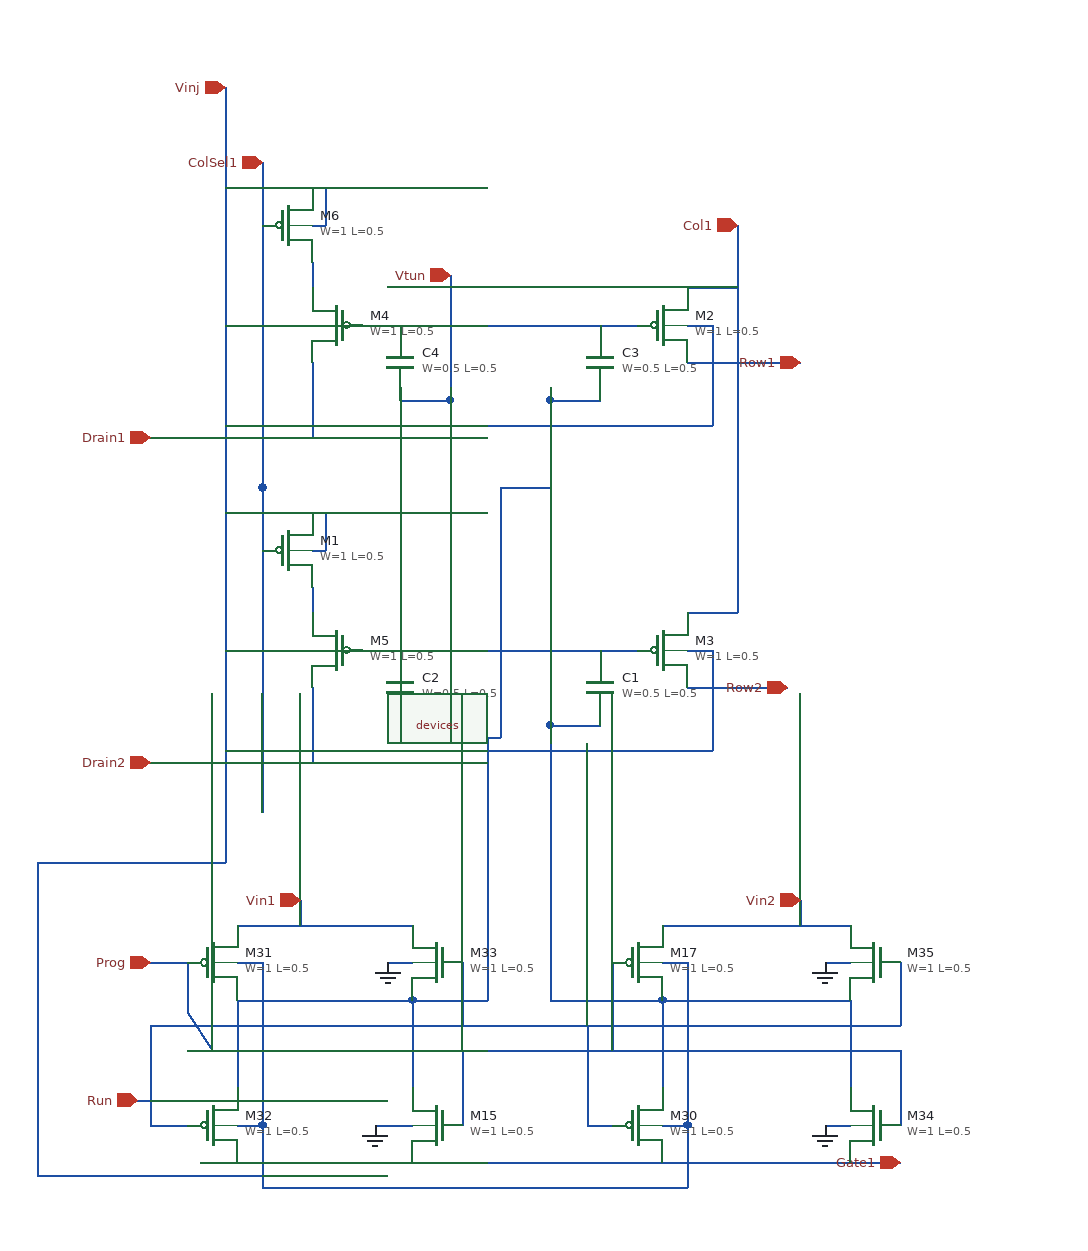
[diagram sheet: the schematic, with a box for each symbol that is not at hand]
v {xschem version=2.9.9 file_version=1.2 }
G {}
K {}
V {}
S {}
E {}
N 1300 -1430 1330 -1430 { lab=#net1}
N 1260 -1380 1260 -1370 { lab=#net2}
N 1260 -1370 1300 -1370 { lab=#net2}
N 1140 -1430 1300 -1430 { lab=#net1}
N 1140 -1370 1180 -1370 { lab=Vtun}
N 1140 -1380 1140 -1370 { lab=Vtun}
N 1110 -1430 1140 -1430 { lab=#net1}
N 1070 -1480 1070 -1460 { lab=#net3}
N 1260 -1370 1260 -1300 { lab=#net2}
N 1180 -1380 1180 -1370 { lab=Vtun}
N 1180 -1560 1180 -1370 { lab=Vtun}
N 1030 -1560 1030 -1510 { lab=ColSel1}
N 1030 -1560 1030 -1300 { lab=ColSel1}
N 1070 -1400 1070 -1340 { lab=Drain2}
N 950 -1340 1070 -1340 { lab=Drain2}
N 1000 -1560 1000 -1300 { lab=Vinj}
N 1000 -1540 1070 -1540 { lab=Vinj}
N 1300 -1690 1330 -1690 { lab=#net4}
N 1260 -1640 1260 -1630 { lab=#net5}
N 1260 -1630 1300 -1630 { lab=#net5}
N 1140 -1690 1300 -1690 { lab=#net4}
N 1140 -1630 1180 -1630 { lab=Vtun}
N 1140 -1640 1140 -1630 { lab=Vtun}
N 1110 -1690 1140 -1690 { lab=#net4}
N 1070 -1740 1070 -1720 { lab=#net6}
N 1370 -1720 1410 -1720 { lab=Col1}
N 1260 -1630 1260 -1560 { lab=#net5}
N 1180 -1640 1180 -1630 { lab=Vtun}
N 1180 -1630 1180 -1560 { lab=Vtun}
N 1030 -1820 1030 -1770 { lab=ColSel1}
N 1030 -1820 1030 -1560 { lab=ColSel1}
N 1070 -1660 1070 -1600 { lab=Drain1}
N 950 -1600 1070 -1600 { lab=Drain1}
N 1000 -1820 1000 -1560 { lab=Vinj}
N 1000 -1800 1070 -1800 { lab=Vinj}
N 930 -1600 960 -1600 { lab=Drain1}
N 930 -1340 960 -1340 { lab=Drain2}
N 1000 -1690 1070 -1690 { lab=Vinj}
N 1070 -1770 1080 -1770 { lab=Vinj}
N 1080 -1800 1080 -1770 { lab=Vinj}
N 1050 -1800 1080 -1800 { lab=Vinj}
N 1000 -1430 1080 -1430 { lab=Vinj}
N 1070 -1510 1080 -1510 { lab=Vinj}
N 1080 -1540 1080 -1510 { lab=Vinj}
N 1050 -1540 1080 -1540 { lab=Vinj}
N 1000 -1350 1390 -1350 { lab=Vinj}
N 1390 -1430 1390 -1350 { lab=Vinj}
N 1370 -1430 1390 -1430 { lab=Vinj}
N 1370 -1690 1390 -1690 { lab=Vinj}
N 1390 -1690 1390 -1610 { lab=Vinj}
N 1000 -1880 1000 -1820 { lab=Vinj}
N 1260 -1300 1260 -1270 { lab=#net2}
N 1220 -1560 1260 -1560 { lab=#net5}
N 1220 -1560 1220 -1460 { lab=#net5}
N 1220 -1460 1220 -1390 { lab=#net5}
N 1220 -1390 1220 -1370 { lab=#net5}
N 1220 -1370 1220 -1360 { lab=#net5}
N 1210 -1360 1220 -1360 { lab=#net5}
N 1210 -1360 1210 -1310 { lab=#net5}
N 1210 -1310 1210 -1230 { lab=#net5}
N 1260 -1270 1260 -1230 { lab=#net2}
N 980 -1020 1540 -1020 { lab=Gate1}
N 1010 -1210 1150 -1210 { lab=Vin1}
N 1010 -1150 1010 -1080 { lab=#net5}
N 1150 -1150 1150 -1080 { lab=#net5}
N 1500 -1150 1500 -1080 { lab=#net2}
N 1350 -1210 1500 -1210 { lab=Vin2}
N 1010 -1150 1150 -1150 { lab=#net5}
N 1350 -1150 1350 -1080 { lab=#net2}
N 1350 -1150 1500 -1150 { lab=#net2}
N 1210 -1230 1210 -1150 { lab=#net5}
N 1150 -1150 1210 -1150 { lab=#net5}
N 1260 -1230 1260 -1150 { lab=#net2}
N 1260 -1150 1350 -1150 { lab=#net2}
N 1060 -1230 1060 -1210 { lab=Vin1}
N 1460 -1230 1460 -1210 { lab=Vin2}
N 1540 -1180 1540 -1130 { lab=Run}
N 1380 -1130 1540 -1130 { lab=Run}
N 1220 -1130 1380 -1130 { lab=Run}
N 1060 -1130 1220 -1130 { lab=Run}
N 970 -1130 1060 -1130 { lab=Run}
N 940 -1130 940 -1050 { lab=Run}
N 930 -1070 940 -1070 { lab=Run}
N 940 -1050 970 -1050 { lab=Run}
N 940 -1130 970 -1130 { lab=Run}
N 940 -1180 970 -1180 { lab=Prog}
N 1540 -1110 1540 -1050 { lab=Prog}
N 970 -1110 1540 -1110 { lab=Prog}
N 970 -1180 970 -1140 { lab=Prog}
N 970 -1140 990 -1110 { lab=Prog}
N 1310 -1180 1310 -1110 { lab=Prog}
N 1290 -1050 1310 -1050 { lab=Run}
N 1290 -1130 1290 -1050 { lab=Run}
N 1190 -1180 1190 -1130 { lab=Run}
N 1190 -1110 1190 -1050 { lab=Prog}
N 1370 -1050 1370 -1000 { lab=Vinj}
N 1350 -1050 1370 -1050 { lab=Vinj}
N 1030 -1050 1030 -1000 { lab=Vinj}
N 1010 -1050 1030 -1050 { lab=Vinj}
N 1370 -1100 1370 -1050 { lab=Vinj}
N 1370 -1120 1370 -1100 { lab=Vinj}
N 1370 -1140 1370 -1120 { lab=Vinj}
N 1370 -1160 1370 -1140 { lab=Vinj}
N 1370 -1180 1370 -1160 { lab=Vinj}
N 1350 -1180 1370 -1180 { lab=Vinj}
N 1030 -1100 1030 -1050 { lab=Vinj}
N 1030 -1120 1030 -1100 { lab=Vinj}
N 1030 -1140 1030 -1120 { lab=Vinj}
N 1030 -1180 1030 -1140 { lab=Vinj}
N 1010 -1180 1030 -1180 { lab=Vinj}
N 1120 -1050 1150 -1050 { lab=GND}
N 1130 -1180 1150 -1180 { lab=GND}
N 1480 -1180 1500 -1180 { lab=GND}
N 1480 -1050 1500 -1050 { lab=GND}
N 1300 -1610 1390 -1610 { lab=Vinj}
N 1210 -1610 1300 -1610 { lab=Vinj}
N 1130 -1610 1210 -1610 { lab=Vinj}
N 1080 -1610 1130 -1610 { lab=Vinj}
N 1050 -1610 1080 -1610 { lab=Vinj}
N 1000 -1610 1050 -1610 { lab=Vinj}
N 1180 -1730 1180 -1630 { lab=Vtun}
N 1030 -1000 1370 -1000 { lab=Vinj}
N 1370 -1400 1450 -1400 { lab=Row2}
N 1410 -1770 1410 -1460 { lab=Col1}
N 1370 -1460 1410 -1460 { lab=Col1}
N 1370 -1660 1460 -1660 { lab=Row1}
N 1000 -1300 1000 -1260 { lab=Vinj}
N 850 -1260 1000 -1260 { lab=Vinj}
N 850 -1260 850 -1010 { lab=Vinj}
N 850 -1010 1030 -1010 { lab=Vinj}
C {sky130_fd_pr/pfet_g5v0d10v5.sym} 1350 -1430 0 0 {name=M3
L=0.5
W=1
nf=1
mult=1
ad="'int((nf+1)/2) * W/nf * 0.29'" 
pd="'2*int((nf+1)/2) * (W/nf + 0.29)'"
as="'int((nf+2)/2) * W/nf * 0.29'" 
ps="'2*int((nf+2)/2) * (W/nf + 0.29)'"
nrd="'0.29 / W'" nrs="'0.29 / W'"
sa=0 sb=0 sd=0
model=pfet_g5v0d10v5
spiceprefix=X
}
C {sky130_fd_pr/cap_var_hvt.sym} 1300 -1400 0 0 {name=C1 model=cap_var_hvt W=0.5 L=0.5 VM=1 spiceprefix=X}
C {sky130_fd_pr/pfet_g5v0d10v5.sym} 1090 -1430 0 1 {name=M5
L=0.5
W=1
nf=1
mult=1
ad="'int((nf+1)/2) * W/nf * 0.29'" 
pd="'2*int((nf+1)/2) * (W/nf + 0.29)'"
as="'int((nf+2)/2) * W/nf * 0.29'" 
ps="'2*int((nf+2)/2) * (W/nf + 0.29)'"
nrd="'0.29 / W'" nrs="'0.29 / W'"
sa=0 sb=0 sd=0
model=pfet_g5v0d10v5
spiceprefix=X
}
C {sky130_fd_pr/cap_var_hvt.sym} 1140 -1400 0 1 {name=C2 model=cap_var_hvt W=0.5 L=0.5 VM=1 spiceprefix=X}
C {sky130_fd_pr/pfet_g5v0d10v5.sym} 1050 -1510 0 0 {name=M1
L=0.5
W=1
nf=1
mult=1
ad="'int((nf+1)/2) * W/nf * 0.29'" 
pd="'2*int((nf+1)/2) * (W/nf + 0.29)'"
as="'int((nf+2)/2) * W/nf * 0.29'" 
ps="'2*int((nf+2)/2) * (W/nf + 0.29)'"
nrd="'0.29 / W'" nrs="'0.29 / W'"
sa=0 sb=0 sd=0
model=pfet_g5v0d10v5
spiceprefix=X
}
C {sky130_fd_pr/pfet_g5v0d10v5.sym} 1350 -1690 0 0 {name=M2
L=0.5
W=1
nf=1
mult=1
ad="'int((nf+1)/2) * W/nf * 0.29'" 
pd="'2*int((nf+1)/2) * (W/nf + 0.29)'"
as="'int((nf+2)/2) * W/nf * 0.29'" 
ps="'2*int((nf+2)/2) * (W/nf + 0.29)'"
nrd="'0.29 / W'" nrs="'0.29 / W'"
sa=0 sb=0 sd=0
model=pfet_g5v0d10v5
spiceprefix=X
}
C {sky130_fd_pr/cap_var_hvt.sym} 1300 -1660 0 0 {name=C3 model=cap_var_hvt W=0.5 L=0.5 VM=1 spiceprefix=X}
C {sky130_fd_pr/pfet_g5v0d10v5.sym} 1090 -1690 0 1 {name=M4
L=0.5
W=1
nf=1
mult=1
ad="'int((nf+1)/2) * W/nf * 0.29'" 
pd="'2*int((nf+1)/2) * (W/nf + 0.29)'"
as="'int((nf+2)/2) * W/nf * 0.29'" 
ps="'2*int((nf+2)/2) * (W/nf + 0.29)'"
nrd="'0.29 / W'" nrs="'0.29 / W'"
sa=0 sb=0 sd=0
model=pfet_g5v0d10v5
spiceprefix=X
}
C {sky130_fd_pr/cap_var_hvt.sym} 1140 -1660 0 1 {name=C4 model=cap_var_hvt W=0.5 L=0.5 VM=1 spiceprefix=X}
C {sky130_fd_pr/pfet_g5v0d10v5.sym} 1050 -1770 0 0 {name=M6
L=0.5
W=1
nf=1
mult=1
ad="'int((nf+1)/2) * W/nf * 0.29'" 
pd="'2*int((nf+1)/2) * (W/nf + 0.29)'"
as="'int((nf+2)/2) * W/nf * 0.29'" 
ps="'2*int((nf+2)/2) * (W/nf + 0.29)'"
nrd="'0.29 / W'" nrs="'0.29 / W'"
sa=0 sb=0 sd=0
model=pfet_g5v0d10v5
spiceprefix=X
}
C {devices} 980 -1480 0 0 {}
C {devices/ipin.sym} 940 -1600 0 0 {name=Drain1 lab=Drain1}
C {devices/ipin.sym} 940 -1340 0 0 {name=Drain2 lab=Drain2}
C {devices/ipin.sym} 930 -1070 0 0 {name=Run lab=Run}
C {devices/ipin.sym} 940 -1180 0 0 {name=Prog lab=Prog}
C {devices/iopin.sym} 1180 -1730 0 0 {name=Vtun lab=Vtun}
C {devices/iopin.sym} 1030 -1820 0 0 {name=ColSel1 lab=ColSel1}
C {devices/iopin.sym} 1000 -1880 0 0 {name=Vinj lab=Vinj}
C {devices/iopin.sym} 1540 -1020 0 0 {name=Gate1 lab=Gate1}
C {sky130_fd_pr/nfet_g5v0d10v5.sym} 1170 -1050 0 1 {name=M15
L=0.5
W=1
nf=1
mult=1
ad="'int((nf+1)/2) * W/nf * 0.29'" 
pd="'2*int((nf+1)/2) * (W/nf + 0.29)'"
as="'int((nf+2)/2) * W/nf * 0.29'" 
ps="'2*int((nf+2)/2) * (W/nf + 0.29)'"
nrd="'0.29 / W'" nrs="'0.29 / W'"
sa=0 sb=0 sd=0
model=nfet_g5v0d10v5
spiceprefix=X
}
C {sky130_fd_pr/pfet_g5v0d10v5.sym} 1330 -1180 0 0 {name=M17
L=0.5
W=1
nf=1
mult=1
ad="'int((nf+1)/2) * W/nf * 0.29'" 
pd="'2*int((nf+1)/2) * (W/nf + 0.29)'"
as="'int((nf+2)/2) * W/nf * 0.29'" 
ps="'2*int((nf+2)/2) * (W/nf + 0.29)'"
nrd="'0.29 / W'" nrs="'0.29 / W'"
sa=0 sb=0 sd=0
model=pfet_g5v0d10v5
spiceprefix=X
}
C {devices/iopin.sym} 1060 -1230 0 0 {name=Vin1 lab=Vin1}
C {devices/iopin.sym} 1460 -1230 0 0 {name=Vin2 lab=Vin2}
C {sky130_fd_pr/pfet_g5v0d10v5.sym} 1330 -1050 0 0 {name=M30
L=0.5
W=1
nf=1
mult=1
ad="'int((nf+1)/2) * W/nf * 0.29'" 
pd="'2*int((nf+1)/2) * (W/nf + 0.29)'"
as="'int((nf+2)/2) * W/nf * 0.29'" 
ps="'2*int((nf+2)/2) * (W/nf + 0.29)'"
nrd="'0.29 / W'" nrs="'0.29 / W'"
sa=0 sb=0 sd=0
model=pfet_g5v0d10v5
spiceprefix=X
}
C {sky130_fd_pr/pfet_g5v0d10v5.sym} 990 -1180 0 0 {name=M31
L=0.5
W=1
nf=1
mult=1
ad="'int((nf+1)/2) * W/nf * 0.29'" 
pd="'2*int((nf+1)/2) * (W/nf + 0.29)'"
as="'int((nf+2)/2) * W/nf * 0.29'" 
ps="'2*int((nf+2)/2) * (W/nf + 0.29)'"
nrd="'0.29 / W'" nrs="'0.29 / W'"
sa=0 sb=0 sd=0
model=pfet_g5v0d10v5
spiceprefix=X
}
C {sky130_fd_pr/pfet_g5v0d10v5.sym} 990 -1050 0 0 {name=M32
L=0.5
W=1
nf=1
mult=1
ad="'int((nf+1)/2) * W/nf * 0.29'" 
pd="'2*int((nf+1)/2) * (W/nf + 0.29)'"
as="'int((nf+2)/2) * W/nf * 0.29'" 
ps="'2*int((nf+2)/2) * (W/nf + 0.29)'"
nrd="'0.29 / W'" nrs="'0.29 / W'"
sa=0 sb=0 sd=0
model=pfet_g5v0d10v5
spiceprefix=X
}
C {sky130_fd_pr/nfet_g5v0d10v5.sym} 1170 -1180 0 1 {name=M33
L=0.5
W=1
nf=1
mult=1
ad="'int((nf+1)/2) * W/nf * 0.29'" 
pd="'2*int((nf+1)/2) * (W/nf + 0.29)'"
as="'int((nf+2)/2) * W/nf * 0.29'" 
ps="'2*int((nf+2)/2) * (W/nf + 0.29)'"
nrd="'0.29 / W'" nrs="'0.29 / W'"
sa=0 sb=0 sd=0
model=nfet_g5v0d10v5
spiceprefix=X
}
C {sky130_fd_pr/nfet_g5v0d10v5.sym} 1520 -1050 0 1 {name=M34
L=0.5
W=1
nf=1
mult=1
ad="'int((nf+1)/2) * W/nf * 0.29'" 
pd="'2*int((nf+1)/2) * (W/nf + 0.29)'"
as="'int((nf+2)/2) * W/nf * 0.29'" 
ps="'2*int((nf+2)/2) * (W/nf + 0.29)'"
nrd="'0.29 / W'" nrs="'0.29 / W'"
sa=0 sb=0 sd=0
model=nfet_g5v0d10v5
spiceprefix=X
}
C {sky130_fd_pr/nfet_g5v0d10v5.sym} 1520 -1180 0 1 {name=M35
L=0.5
W=1
nf=1
mult=1
ad="'int((nf+1)/2) * W/nf * 0.29'" 
pd="'2*int((nf+1)/2) * (W/nf + 0.29)'"
as="'int((nf+2)/2) * W/nf * 0.29'" 
ps="'2*int((nf+2)/2) * (W/nf + 0.29)'"
nrd="'0.29 / W'" nrs="'0.29 / W'"
sa=0 sb=0 sd=0
model=nfet_g5v0d10v5
spiceprefix=X
}
C {devices/gnd.sym} 1480 -1050 0 0 {name=l3 lab=GND}
C {devices/gnd.sym} 1480 -1180 0 0 {name=l4 lab=GND}
C {devices/gnd.sym} 1130 -1180 0 0 {name=l5 lab=GND}
C {devices/gnd.sym} 1120 -1050 0 0 {name=l6 lab=GND}
C {devices/iopin.sym} 1410 -1770 0 0 {name=Col1 lab=Col1}
C {devices/iopin.sym} 1450 -1400 0 0 {name=Row1 lab=Row2}
C {devices/iopin.sym} 1460 -1660 0 0 {name=Row2 lab=Row1}
